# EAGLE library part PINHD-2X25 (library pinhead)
PIN HEADER

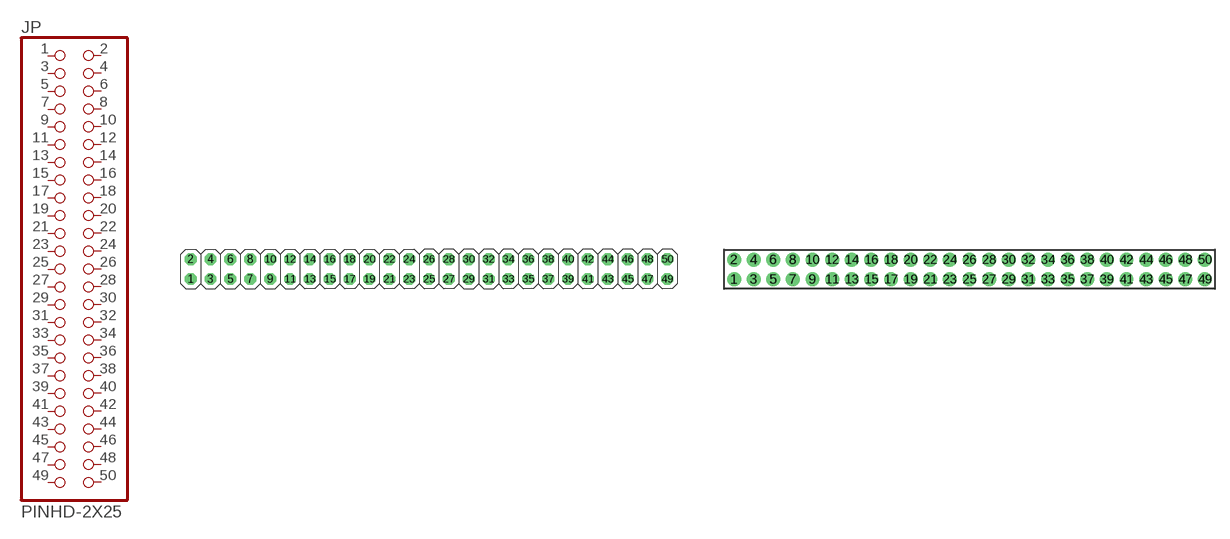
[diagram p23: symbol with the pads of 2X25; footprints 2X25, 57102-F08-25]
Designator prefix JP

## PINHD-2X25  [2X25]
1  1  pas
2  2  pas
3  3  pas
4  4  pas
5  5  pas
6  6  pas
7  7  pas
8  8  pas
9  9  pas
10  10  pas
11  11  pas
12  12  pas
13  13  pas
14  14  pas
15  15  pas
16  16  pas
17  17  pas
18  18  pas
19  19  pas
20  20  pas
21  21  pas
22  22  pas
23  23  pas
24  24  pas
25  25  pas
26  26  pas
27  27  pas
28  28  pas
29  29  pas
30  30  pas
31  31  pas
32  32  pas
33  33  pas
34  34  pas
35  35  pas
36  36  pas
37  37  pas
38  38  pas
39  39  pas
40  40  pas
41  41  pas
42  42  pas
43  43  pas
44  44  pas
45  45  pas
46  46  pas
47  47  pas
48  48  pas
49  49  pas
50  50  pas

## PINHD-2X25_57102-F08-25  [57102-F08-25]
Pads as for 2X25

## Footprint 2X25 (pad centres in mm)
PIN HEADER
drill 1.016 octagon: 1 -30.48,-1.27; 2 -30.48,1.27; 3 -27.94,-1.27; 4 -27.94,1.27; 5 -25.4,-1.27; 6 -25.4,1.27; 7 -22.86,-1.27; 8 -22.86,1.27; 9 -20.32,-1.27; 10 -20.32,1.27; 11 -17.78,-1.27; 12 -17.78,1.27; 13 -15.24,-1.27; 14 -15.24,1.27; 15 -12.7,-1.27; 16 -12.7,1.27; 17 -10.16,-1.27; 18 -10.16,1.27; 19 -7.62,-1.27; 20 -7.62,1.27; 21 -5.08,-1.27; 22 -5.08,1.27; 23 -2.54,-1.27; 24 -2.54,1.27; 25 0,-1.27; 26 0,1.27; 27 2.54,-1.27; 28 2.54,1.27; 29 5.08,-1.27; 30 5.08,1.27; 31 7.62,-1.27; 32 7.62,1.27; 33 10.16,-1.27; 34 10.16,1.27; 35 12.7,-1.27; 36 12.7,1.27; 37 15.24,-1.27; 38 15.24,1.27; 39 17.78,-1.27; 40 17.78,1.27; 41 20.32,-1.27; 42 20.32,1.27; 43 22.86,-1.27; 44 22.86,1.27; 45 25.4,-1.27; 46 25.4,1.27; 47 27.94,-1.27; 48 27.94,1.27; 49 30.48,-1.27; 50 30.48,1.27

## Footprint 57102-F08-25 (pad centres in mm)
UNSH HEADER 2.0mm VERTICAL TMT Source: https://portal.fciconnect.com/res/en/pdffiles/doc_search/57102.pdf
drill 0.8 pad 1.422 round: 1 -9,-1; 2 -9,1; 3 -7,-1; 4 -7,1; 5 -5,-1; 6 -5,1; 7 -3,-1; 8 -3,1; 9 -1,-1; 10 -1,1; 11 1,-1; 12 1,1; 13 3,-1; 14 3,1; 15 5,-1; 16 5,1; 17 7,-1; 18 7,1; 19 9,-1; 20 9,1; 21 11,-1; 22 11,1; 23 13,-1; 24 13,1; 25 15,-1; 26 15,1; 27 17,-1; 28 17,1; 29 19,-1; 30 19,1; 31 21,-1; 32 21,1; 33 23,-1; 34 23,1; 35 25,-1; 36 25,1; 37 27,-1; 38 27,1; 39 29,-1; 40 29,1; 41 31,-1; 42 31,1; 43 33,-1; 44 33,1; 45 35,-1; 46 35,1; 47 37,-1; 48 37,1; 49 39,-1; 50 39,1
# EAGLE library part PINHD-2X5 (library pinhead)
PIN HEADER

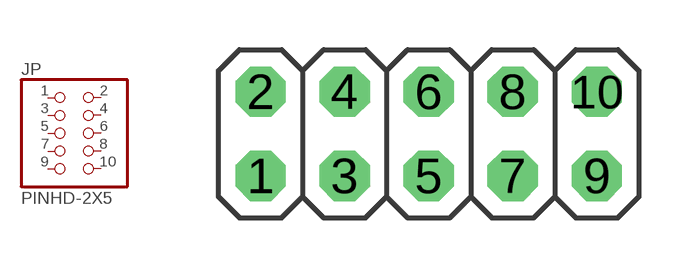
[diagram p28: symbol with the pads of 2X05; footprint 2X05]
Designator prefix JP

## PINHD-2X5  [2X05]
1  1  pas
2  2  pas
3  3  pas
4  4  pas
5  5  pas
6  6  pas
7  7  pas
8  8  pas
9  9  pas
10  10  pas

## Footprint 2X05 (pad centres in mm)
PIN HEADER
drill 1.016 octagon: 1 -5.08,-1.27; 2 -5.08,1.27; 3 -2.54,-1.27; 4 -2.54,1.27; 5 0,-1.27; 6 0,1.27; 7 2.54,-1.27; 8 2.54,1.27; 9 5.08,-1.27; 10 5.08,1.27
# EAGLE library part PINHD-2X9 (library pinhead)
PIN HEADER

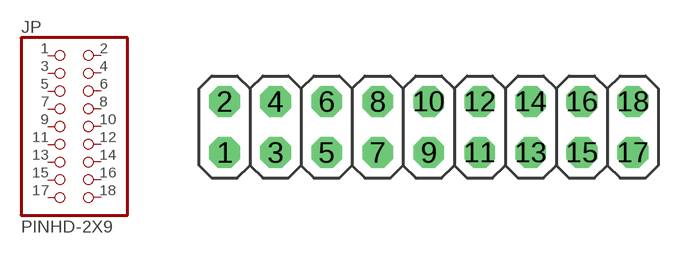
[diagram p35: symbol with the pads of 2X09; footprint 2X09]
Designator prefix JP

## PINHD-2X9  [2X09]
1  1  pas
2  2  pas
3  3  pas
4  4  pas
5  5  pas
6  6  pas
7  7  pas
8  8  pas
9  9  pas
10  10  pas
11  11  pas
12  12  pas
13  13  pas
14  14  pas
15  15  pas
16  16  pas
17  17  pas
18  18  pas

## Footprint 2X09 (pad centres in mm)
PIN HEADER
drill 1.016 octagon: 1 -10.16,-1.27; 2 -10.16,1.27; 3 -7.62,-1.27; 4 -7.62,1.27; 5 -5.08,-1.27; 6 -5.08,1.27; 7 -2.54,-1.27; 8 -2.54,1.27; 9 0,-1.27; 10 0,1.27; 11 2.54,-1.27; 12 2.54,1.27; 13 5.08,-1.27; 14 5.08,1.27; 15 7.62,-1.27; 16 7.62,1.27; 17 10.16,-1.27; 18 10.16,1.27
